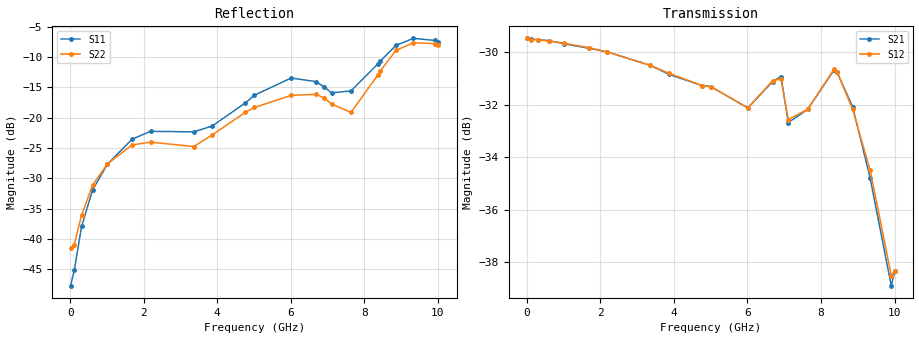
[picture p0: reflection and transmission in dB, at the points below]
! Device ID: PE43705
! Serial: 1
! Insertion: A
! Impedance: 50 ohm
! Temp: 25C
! VDD: 3.400V
! Attenuation Step: 28.50dB
#  Hz  S  RI  R  50
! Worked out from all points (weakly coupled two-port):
!   401 points, 10 MHz to 10.01 GHz, reference 50 ohm
!   highest |S21| = -29.48 dB at 10 MHz (marker M1); lowest = -38.9 dB at 9.91 GHz (marker M2)
!   lowest |S11| = -47.7 dB at 10 MHz (marker M3), VSWR 1.01, Z = 49.6 + j0.039 ohm
!   |S11| at or under -10 dB: start of sweep to 8.524 GHz
!   |S22| runs from -41.7 to -7.5 dB; largest |S21 - S12| = 0.0007
!   S11 on the Smith chart (normalised r, x): 10 MHz: 0.99, +0.00; 4.76 GHz: 0.79, +0.12; 8.435 GHz: 0.79, +0.50; 9.335 GHz: 0.51, +0.53; 10.01 GHz: 0.46, +0.30
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1e7  -0.0041 0.000393  0.0336 -0.000148  0.0336 -0.000124  -0.00837 0.000518
1.1e8  -0.00383 0.00395  0.0335 -0.000949  0.0334 -0.000908  -0.00771 0.00462
3.1e8  -0.00647 0.0109  0.0333 -0.00262  0.0333 -0.00259  -0.00968 0.0124
6.1e8  -0.0161 0.0197  0.0329 -0.00495  0.0328 -0.00496  -0.0173 0.0218
1.01e9  -0.0351 0.0216  0.0318 -0.00807  0.0319 -0.00803  -0.0328 0.0253
1.685e9  -0.0659 0.0087  0.0296 -0.0126  0.0297 -0.0126  -0.0569 0.0177
2.185e9  -0.0768 -0.00664  0.0275 -0.0157  0.0275 -0.0157  -0.0623 0.00751
3.36e9  -0.0761 -0.00545  0.0211 -0.0211  0.0212 -0.021  -0.0565 0.0121
3.86e9  -0.0831 0.0191  0.0183 -0.0221  0.0184 -0.0222  -0.0667 0.0268
4.76e9  -0.1107 0.0718  0.0141 -0.0234  0.0141 -0.0234  -0.0937 0.0583
5.01e9  -0.1261 0.0865  0.0133 -0.0237  0.0133 -0.0237  -0.1027 0.0643
6.01e9  -0.1816 0.1096  0.0081 -0.0234  0.00811 -0.0234  -0.1304 0.0792
6.685e9  -0.1729 0.0961  0.00621 -0.0271  0.00626 -0.0272  -0.1373 0.0731
6.91e9  -0.1539 0.0907  0.00256 -0.0283  0.00257 -0.028  -0.1257 0.0727
7.11e9  -0.1383 0.0801  0.00101 -0.0232  0.00117 -0.0235  -0.1051 0.0755
7.635e9  -0.0907 0.139  0.00229 -0.0245  0.00237 -0.0245  -0.0557 0.0954
8.36e9  -0.0328 0.2737  -0.00669 -0.0285  -0.00636 -0.0287  -0.0367 0.2199
8.435e9  -0.0352 0.2911  -0.00813 -0.0278  -0.00791 -0.0279  -0.0397 0.2393
8.86e9  -0.0872 0.3837  -0.0127 -0.0214  -0.0125 -0.0212  -0.0972 0.3449
9.335e9  -0.1822 0.4113  -0.0114 -0.0142  -0.0119 -0.0146  -0.1948 0.3649
9.91e9  -0.3033 0.3085  -0.00349 -0.0108  -0.0033 -0.0114  -0.3305 0.2374
1.001e10  -0.3159 0.2752  -0.00164 -0.012  -0.00165 -0.012  -0.3469 0.1984
